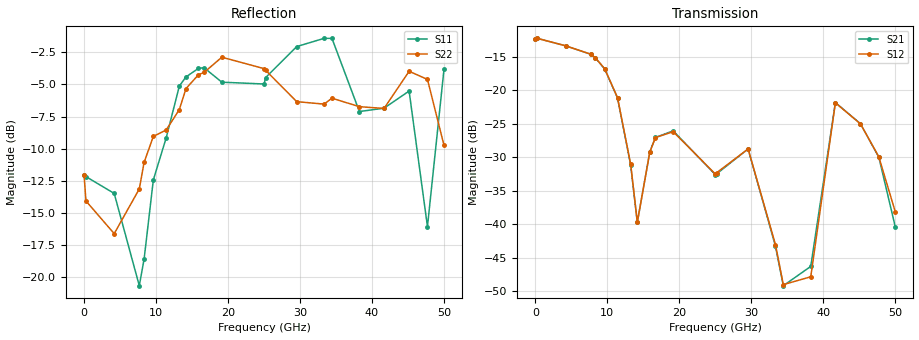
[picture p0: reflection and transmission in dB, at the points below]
!Keysight Technologies,N5245B,MY58422270,A.16.20.02
!Date: Thursday, March 05, 2026 00:56:15
!Correction: S11(C  2-Port  )
!S21(C  2-Port  )
!S12(C  2-Port  )
!S22(C  2-Port  )
!S2P File: Measurements: S11, S21, S12, S22:
# Hz S  dB  R 50
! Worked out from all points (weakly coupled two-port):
!   3201 points, 10 MHz to 50 GHz, reference 50 ohm
!   highest |S21| = -12.26 dB at 275.6 MHz (marker M1); lowest = -49.2 dB at 34.44 GHz (marker M2)
!   lowest |S11| = -20.7 dB at 7.68 GHz (marker M3), VSWR 1.20, Z = 41.6 - j0.923 ohm
!   |S11| at or under -10 dB: start of sweep to 10.37 GHz; 46.72 GHz to 48.26 GHz (1.537 GHz wide, 3.24 % of centre)
!   |S22| runs from -21.1 to -2.4 dB; largest |S21 - S12| = 0.0091
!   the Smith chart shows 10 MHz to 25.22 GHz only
!   S11 on the Smith chart (normalised r, x): 10 MHz: 1.67, -0.02; 9.633 GHz: 0.61, -0.01; 13.24 GHz: 0.75, +1.12; 15.9 GHz: 3.04, -2.17; 19.15 GHz: 0.42, -0.70; 25.22 GHz: 0.25, +0.06
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1e7  -12.04 -1.4  -12.29 4.6  -12.31 3.9  -12.07 32.7
2.755719e8  -12.19 -9.9  -12.26 -11.2  -12.26 -11.2  -14.09 -9.3
4.196662e9  -13.50 -133.5  -13.37 -173.7  -13.37 -173.6  -16.64 -152.6
7.680341e9  -20.70 -173.2  -14.63 32.3  -14.62 32.4  -13.15 -137.0
8.352081e9  -18.61 -159.9  -15.19 1.1  -15.18 1.2  -11.07 -154.6
9.633075e9  -12.44 -178.3  -16.83 -58.5  -16.81 -58.6  -9.05 162.9
1.141397e10  -9.17 120.4  -21.15 -139.9  -21.12 -140.0  -8.55 80.3
1.324173e10  -5.12 69.9  -31.19 152.2  -31.08 152.4  -6.96 -20.4
1.416342e10  -4.41 37.7  -39.75 -175.6  -39.74 -175.8  -5.32 -66.0
1.589745e10  -3.74 -18.5  -29.22 -172.6  -29.24 -172.5  -4.24 -124.3
1.667854e10  -3.69 -41.9  -27.06 160.5  -27.08 160.2  -4.06 -142.7
1.91468e10  -4.82 -103.5  -26.08 78.7  -26.20 78.7  -2.87 174.4
2.5005e10  -4.96 174.8  -32.63 -65.0  -32.53 -65.3  -3.76 70.3
2.522371e10  -4.46 172.1  -32.46 -67.6  -32.30 -67.9  -3.89 65.1
2.955097e10  -2.04 95.5  -28.78 170.1  -28.78 169.8  -6.34 -19.5
3.334708e10  -1.40 35.7  -43.30 1.2  -43.06 -0.4  -6.53 -132.1
3.444061e10  -1.40 16.5  -49.21 -116.4  -49.05 -104.1  -6.07 -156.5
3.825235e10  -7.11 -21.8  -46.33 85.1  -47.88 -96.9  -6.73 132.9
4.167354e10  -6.85 -54.9  -21.85 -58.9  -21.88 -58.8  -6.87 112.5
4.515722e10  -5.51 -102.1  -25.02 88.6  -25.04 88.3  -3.97 74.4
4.770358e10  -16.09 71.8  -30.00 -16.8  -29.95 -15.0  -4.60 40.8
5e10  -3.82 -72.1  -40.45 -121.3  -38.20 -128.6  -9.74 6.8
